VERSION 5.7 ;
  NOWIREEXTENSIONATPIN ON ;
  DIVIDERCHAR "/" ;
  BUSBITCHARS "[]" ;
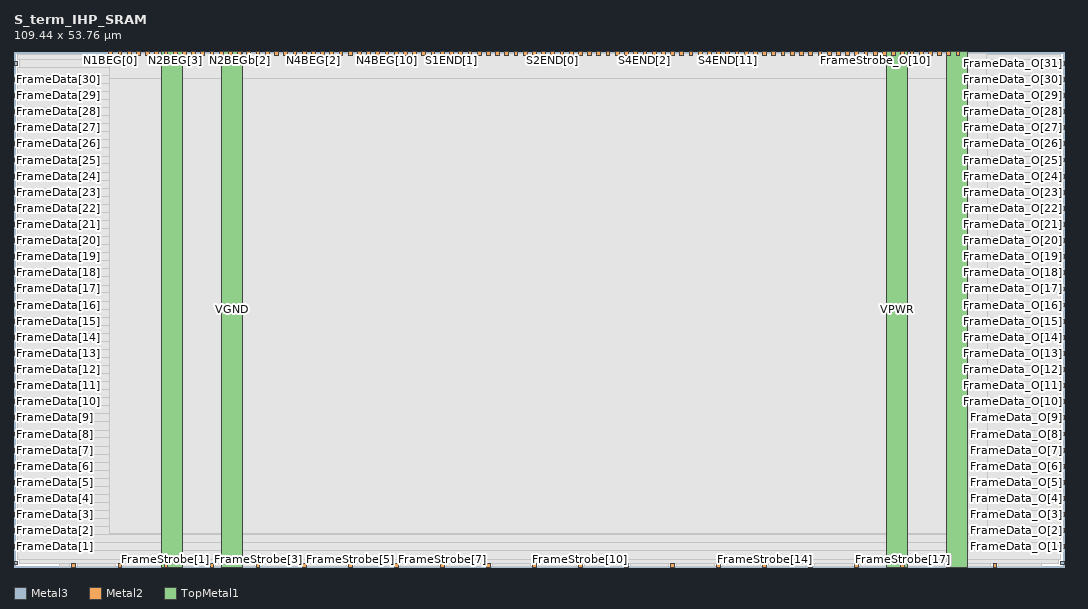
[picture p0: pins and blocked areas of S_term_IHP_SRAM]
MACRO S_term_IHP_SRAM
  CLASS BLOCK ;
  FOREIGN S_term_IHP_SRAM ;
  ORIGIN 0.000 0.000 ;
  SIZE 109.440 BY 53.760 ;
  PIN FrameData[0]
    DIRECTION INPUT ;
    USE SIGNAL ;
    ANTENNAGATEAREA 0.180700 ;
    PORT
      LAYER Metal3 ;
        RECT 0.000 0.220 0.400 0.620 ;
    END
  END FrameData[0]
  PIN FrameData[10]
    DIRECTION INPUT ;
    USE SIGNAL ;
    ANTENNAGATEAREA 0.180700 ;
    PORT
      LAYER Metal3 ;
        RECT 0.000 17.020 0.400 17.420 ;
    END
  END FrameData[10]
  PIN FrameData[11]
    DIRECTION INPUT ;
    USE SIGNAL ;
    ANTENNAGATEAREA 0.180700 ;
    PORT
      LAYER Metal3 ;
        RECT 0.000 18.700 0.400 19.100 ;
    END
  END FrameData[11]
  PIN FrameData[12]
    DIRECTION INPUT ;
    USE SIGNAL ;
    ANTENNAGATEAREA 0.180700 ;
    PORT
      LAYER Metal3 ;
        RECT 0.000 20.380 0.400 20.780 ;
    END
  END FrameData[12]
  PIN FrameData[13]
    DIRECTION INPUT ;
    USE SIGNAL ;
    ANTENNAGATEAREA 0.180700 ;
    PORT
      LAYER Metal3 ;
        RECT 0.000 22.060 0.400 22.460 ;
    END
  END FrameData[13]
  PIN FrameData[14]
    DIRECTION INPUT ;
    USE SIGNAL ;
    ANTENNAGATEAREA 0.180700 ;
    PORT
      LAYER Metal3 ;
        RECT 0.000 23.740 0.400 24.140 ;
    END
  END FrameData[14]
  PIN FrameData[15]
    DIRECTION INPUT ;
    USE SIGNAL ;
    ANTENNAGATEAREA 0.180700 ;
    PORT
      LAYER Metal3 ;
        RECT 0.000 25.420 0.400 25.820 ;
    END
  END FrameData[15]
  PIN FrameData[16]
    DIRECTION INPUT ;
    USE SIGNAL ;
    ANTENNAGATEAREA 0.180700 ;
    PORT
      LAYER Metal3 ;
        RECT 0.000 27.100 0.400 27.500 ;
    END
  END FrameData[16]
  PIN FrameData[17]
    DIRECTION INPUT ;
    USE SIGNAL ;
    ANTENNAGATEAREA 0.180700 ;
    PORT
      LAYER Metal3 ;
        RECT 0.000 28.780 0.400 29.180 ;
    END
  END FrameData[17]
  PIN FrameData[18]
    DIRECTION INPUT ;
    USE SIGNAL ;
    ANTENNAGATEAREA 0.180700 ;
    PORT
      LAYER Metal3 ;
        RECT 0.000 30.460 0.400 30.860 ;
    END
  END FrameData[18]
  PIN FrameData[19]
    DIRECTION INPUT ;
    USE SIGNAL ;
    ANTENNAGATEAREA 0.180700 ;
    PORT
      LAYER Metal3 ;
        RECT 0.000 32.140 0.400 32.540 ;
    END
  END FrameData[19]
  PIN FrameData[1]
    DIRECTION INPUT ;
    USE SIGNAL ;
    ANTENNAGATEAREA 0.180700 ;
    PORT
      LAYER Metal3 ;
        RECT 0.000 1.900 0.400 2.300 ;
    END
  END FrameData[1]
  PIN FrameData[20]
    DIRECTION INPUT ;
    USE SIGNAL ;
    ANTENNAGATEAREA 0.180700 ;
    PORT
      LAYER Metal3 ;
        RECT 0.000 33.820 0.400 34.220 ;
    END
  END FrameData[20]
  PIN FrameData[21]
    DIRECTION INPUT ;
    USE SIGNAL ;
    ANTENNAGATEAREA 0.180700 ;
    PORT
      LAYER Metal3 ;
        RECT 0.000 35.500 0.400 35.900 ;
    END
  END FrameData[21]
  PIN FrameData[22]
    DIRECTION INPUT ;
    USE SIGNAL ;
    ANTENNAGATEAREA 0.180700 ;
    PORT
      LAYER Metal3 ;
        RECT 0.000 37.180 0.400 37.580 ;
    END
  END FrameData[22]
  PIN FrameData[23]
    DIRECTION INPUT ;
    USE SIGNAL ;
    ANTENNAGATEAREA 0.180700 ;
    PORT
      LAYER Metal3 ;
        RECT 0.000 38.860 0.400 39.260 ;
    END
  END FrameData[23]
  PIN FrameData[24]
    DIRECTION INPUT ;
    USE SIGNAL ;
    ANTENNAGATEAREA 0.180700 ;
    PORT
      LAYER Metal3 ;
        RECT 0.000 40.540 0.400 40.940 ;
    END
  END FrameData[24]
  PIN FrameData[25]
    DIRECTION INPUT ;
    USE SIGNAL ;
    ANTENNAGATEAREA 0.180700 ;
    PORT
      LAYER Metal3 ;
        RECT 0.000 42.220 0.400 42.620 ;
    END
  END FrameData[25]
  PIN FrameData[26]
    DIRECTION INPUT ;
    USE SIGNAL ;
    ANTENNAGATEAREA 0.180700 ;
    PORT
      LAYER Metal3 ;
        RECT 0.000 43.900 0.400 44.300 ;
    END
  END FrameData[26]
  PIN FrameData[27]
    DIRECTION INPUT ;
    USE SIGNAL ;
    ANTENNAGATEAREA 0.180700 ;
    PORT
      LAYER Metal3 ;
        RECT 0.000 45.580 0.400 45.980 ;
    END
  END FrameData[27]
  PIN FrameData[28]
    DIRECTION INPUT ;
    USE SIGNAL ;
    ANTENNAGATEAREA 0.180700 ;
    PORT
      LAYER Metal3 ;
        RECT 0.000 47.260 0.400 47.660 ;
    END
  END FrameData[28]
  PIN FrameData[29]
    DIRECTION INPUT ;
    USE SIGNAL ;
    ANTENNAGATEAREA 0.180700 ;
    PORT
      LAYER Metal3 ;
        RECT 0.000 48.940 0.400 49.340 ;
    END
  END FrameData[29]
  PIN FrameData[2]
    DIRECTION INPUT ;
    USE SIGNAL ;
    ANTENNAGATEAREA 0.180700 ;
    PORT
      LAYER Metal3 ;
        RECT 0.000 3.580 0.400 3.980 ;
    END
  END FrameData[2]
  PIN FrameData[30]
    DIRECTION INPUT ;
    USE SIGNAL ;
    ANTENNAGATEAREA 0.180700 ;
    PORT
      LAYER Metal3 ;
        RECT 0.000 50.620 0.400 51.020 ;
    END
  END FrameData[30]
  PIN FrameData[31]
    DIRECTION INPUT ;
    USE SIGNAL ;
    ANTENNAGATEAREA 0.180700 ;
    PORT
      LAYER Metal3 ;
        RECT 0.000 52.300 0.400 52.700 ;
    END
  END FrameData[31]
  PIN FrameData[3]
    DIRECTION INPUT ;
    USE SIGNAL ;
    ANTENNAGATEAREA 0.180700 ;
    PORT
      LAYER Metal3 ;
        RECT 0.000 5.260 0.400 5.660 ;
    END
  END FrameData[3]
  PIN FrameData[4]
    DIRECTION INPUT ;
    USE SIGNAL ;
    ANTENNAGATEAREA 0.180700 ;
    PORT
      LAYER Metal3 ;
        RECT 0.000 6.940 0.400 7.340 ;
    END
  END FrameData[4]
  PIN FrameData[5]
    DIRECTION INPUT ;
    USE SIGNAL ;
    ANTENNAGATEAREA 0.180700 ;
    PORT
      LAYER Metal3 ;
        RECT 0.000 8.620 0.400 9.020 ;
    END
  END FrameData[5]
  PIN FrameData[6]
    DIRECTION INPUT ;
    USE SIGNAL ;
    ANTENNAGATEAREA 0.180700 ;
    PORT
      LAYER Metal3 ;
        RECT 0.000 10.300 0.400 10.700 ;
    END
  END FrameData[6]
  PIN FrameData[7]
    DIRECTION INPUT ;
    USE SIGNAL ;
    ANTENNAGATEAREA 0.180700 ;
    PORT
      LAYER Metal3 ;
        RECT 0.000 11.980 0.400 12.380 ;
    END
  END FrameData[7]
  PIN FrameData[8]
    DIRECTION INPUT ;
    USE SIGNAL ;
    ANTENNAGATEAREA 0.180700 ;
    PORT
      LAYER Metal3 ;
        RECT 0.000 13.660 0.400 14.060 ;
    END
  END FrameData[8]
  PIN FrameData[9]
    DIRECTION INPUT ;
    USE SIGNAL ;
    ANTENNAGATEAREA 0.180700 ;
    PORT
      LAYER Metal3 ;
        RECT 0.000 15.340 0.400 15.740 ;
    END
  END FrameData[9]
  PIN FrameData_O[0]
    DIRECTION OUTPUT ;
    USE SIGNAL ;
    ANTENNADIFFAREA 0.708600 ;
    PORT
      LAYER Metal3 ;
        RECT 109.040 0.220 109.440 0.620 ;
    END
  END FrameData_O[0]
  PIN FrameData_O[10]
    DIRECTION OUTPUT ;
    USE SIGNAL ;
    ANTENNADIFFAREA 0.708600 ;
    PORT
      LAYER Metal3 ;
        RECT 109.040 17.020 109.440 17.420 ;
    END
  END FrameData_O[10]
  PIN FrameData_O[11]
    DIRECTION OUTPUT ;
    USE SIGNAL ;
    ANTENNADIFFAREA 0.708600 ;
    PORT
      LAYER Metal3 ;
        RECT 109.040 18.700 109.440 19.100 ;
    END
  END FrameData_O[11]
  PIN FrameData_O[12]
    DIRECTION OUTPUT ;
    USE SIGNAL ;
    ANTENNADIFFAREA 0.708600 ;
    PORT
      LAYER Metal3 ;
        RECT 109.040 20.380 109.440 20.780 ;
    END
  END FrameData_O[12]
  PIN FrameData_O[13]
    DIRECTION OUTPUT ;
    USE SIGNAL ;
    ANTENNADIFFAREA 0.708600 ;
    PORT
      LAYER Metal3 ;
        RECT 109.040 22.060 109.440 22.460 ;
    END
  END FrameData_O[13]
  PIN FrameData_O[14]
    DIRECTION OUTPUT ;
    USE SIGNAL ;
    ANTENNADIFFAREA 0.708600 ;
    PORT
      LAYER Metal3 ;
        RECT 109.040 23.740 109.440 24.140 ;
    END
  END FrameData_O[14]
  PIN FrameData_O[15]
    DIRECTION OUTPUT ;
    USE SIGNAL ;
    ANTENNADIFFAREA 0.708600 ;
    PORT
      LAYER Metal3 ;
        RECT 109.040 25.420 109.440 25.820 ;
    END
  END FrameData_O[15]
  PIN FrameData_O[16]
    DIRECTION OUTPUT ;
    USE SIGNAL ;
    ANTENNADIFFAREA 0.708600 ;
    PORT
      LAYER Metal3 ;
        RECT 109.040 27.100 109.440 27.500 ;
    END
  END FrameData_O[16]
  PIN FrameData_O[17]
    DIRECTION OUTPUT ;
    USE SIGNAL ;
    ANTENNADIFFAREA 0.708600 ;
    PORT
      LAYER Metal3 ;
        RECT 109.040 28.780 109.440 29.180 ;
    END
  END FrameData_O[17]
  PIN FrameData_O[18]
    DIRECTION OUTPUT ;
    USE SIGNAL ;
    ANTENNADIFFAREA 0.708600 ;
    PORT
      LAYER Metal3 ;
        RECT 109.040 30.460 109.440 30.860 ;
    END
  END FrameData_O[18]
  PIN FrameData_O[19]
    DIRECTION OUTPUT ;
    USE SIGNAL ;
    ANTENNADIFFAREA 0.708600 ;
    PORT
      LAYER Metal3 ;
        RECT 109.040 32.140 109.440 32.540 ;
    END
  END FrameData_O[19]
  PIN FrameData_O[1]
    DIRECTION OUTPUT ;
    USE SIGNAL ;
    ANTENNADIFFAREA 0.708600 ;
    PORT
      LAYER Metal3 ;
        RECT 109.040 1.900 109.440 2.300 ;
    END
  END FrameData_O[1]
  PIN FrameData_O[20]
    DIRECTION OUTPUT ;
    USE SIGNAL ;
    ANTENNADIFFAREA 0.708600 ;
    PORT
      LAYER Metal3 ;
        RECT 109.040 33.820 109.440 34.220 ;
    END
  END FrameData_O[20]
  PIN FrameData_O[21]
    DIRECTION OUTPUT ;
    USE SIGNAL ;
    ANTENNADIFFAREA 0.708600 ;
    PORT
      LAYER Metal3 ;
        RECT 109.040 35.500 109.440 35.900 ;
    END
  END FrameData_O[21]
  PIN FrameData_O[22]
    DIRECTION OUTPUT ;
    USE SIGNAL ;
    ANTENNADIFFAREA 0.708600 ;
    PORT
      LAYER Metal3 ;
        RECT 109.040 37.180 109.440 37.580 ;
    END
  END FrameData_O[22]
  PIN FrameData_O[23]
    DIRECTION OUTPUT ;
    USE SIGNAL ;
    ANTENNADIFFAREA 0.708600 ;
    PORT
      LAYER Metal3 ;
        RECT 109.040 38.860 109.440 39.260 ;
    END
  END FrameData_O[23]
  PIN FrameData_O[24]
    DIRECTION OUTPUT ;
    USE SIGNAL ;
    ANTENNADIFFAREA 0.708600 ;
    PORT
      LAYER Metal3 ;
        RECT 109.040 40.540 109.440 40.940 ;
    END
  END FrameData_O[24]
  PIN FrameData_O[25]
    DIRECTION OUTPUT ;
    USE SIGNAL ;
    ANTENNADIFFAREA 0.708600 ;
    PORT
      LAYER Metal3 ;
        RECT 109.040 42.220 109.440 42.620 ;
    END
  END FrameData_O[25]
  PIN FrameData_O[26]
    DIRECTION OUTPUT ;
    USE SIGNAL ;
    ANTENNADIFFAREA 0.708600 ;
    PORT
      LAYER Metal3 ;
        RECT 109.040 43.900 109.440 44.300 ;
    END
  END FrameData_O[26]
  PIN FrameData_O[27]
    DIRECTION OUTPUT ;
    USE SIGNAL ;
    ANTENNADIFFAREA 0.708600 ;
    PORT
      LAYER Metal3 ;
        RECT 109.040 45.580 109.440 45.980 ;
    END
  END FrameData_O[27]
  PIN FrameData_O[28]
    DIRECTION OUTPUT ;
    USE SIGNAL ;
    ANTENNADIFFAREA 0.708600 ;
    PORT
      LAYER Metal3 ;
        RECT 109.040 47.260 109.440 47.660 ;
    END
  END FrameData_O[28]
  PIN FrameData_O[29]
    DIRECTION OUTPUT ;
    USE SIGNAL ;
    ANTENNADIFFAREA 0.708600 ;
    PORT
      LAYER Metal3 ;
        RECT 109.040 48.940 109.440 49.340 ;
    END
  END FrameData_O[29]
  PIN FrameData_O[2]
    DIRECTION OUTPUT ;
    USE SIGNAL ;
    ANTENNADIFFAREA 0.708600 ;
    PORT
      LAYER Metal3 ;
        RECT 109.040 3.580 109.440 3.980 ;
    END
  END FrameData_O[2]
  PIN FrameData_O[30]
    DIRECTION OUTPUT ;
    USE SIGNAL ;
    ANTENNADIFFAREA 0.708600 ;
    PORT
      LAYER Metal3 ;
        RECT 109.040 50.620 109.440 51.020 ;
    END
  END FrameData_O[30]
  PIN FrameData_O[31]
    DIRECTION OUTPUT ;
    USE SIGNAL ;
    ANTENNADIFFAREA 0.708600 ;
    PORT
      LAYER Metal3 ;
        RECT 109.040 52.300 109.440 52.700 ;
    END
  END FrameData_O[31]
  PIN FrameData_O[3]
    DIRECTION OUTPUT ;
    USE SIGNAL ;
    ANTENNADIFFAREA 0.708600 ;
    PORT
      LAYER Metal3 ;
        RECT 109.040 5.260 109.440 5.660 ;
    END
  END FrameData_O[3]
  PIN FrameData_O[4]
    DIRECTION OUTPUT ;
    USE SIGNAL ;
    ANTENNADIFFAREA 0.708600 ;
    PORT
      LAYER Metal3 ;
        RECT 109.040 6.940 109.440 7.340 ;
    END
  END FrameData_O[4]
  PIN FrameData_O[5]
    DIRECTION OUTPUT ;
    USE SIGNAL ;
    ANTENNADIFFAREA 0.708600 ;
    PORT
      LAYER Metal3 ;
        RECT 109.040 8.620 109.440 9.020 ;
    END
  END FrameData_O[5]
  PIN FrameData_O[6]
    DIRECTION OUTPUT ;
    USE SIGNAL ;
    ANTENNADIFFAREA 0.708600 ;
    PORT
      LAYER Metal3 ;
        RECT 109.040 10.300 109.440 10.700 ;
    END
  END FrameData_O[6]
  PIN FrameData_O[7]
    DIRECTION OUTPUT ;
    USE SIGNAL ;
    ANTENNADIFFAREA 0.708600 ;
    PORT
      LAYER Metal3 ;
        RECT 109.040 11.980 109.440 12.380 ;
    END
  END FrameData_O[7]
  PIN FrameData_O[8]
    DIRECTION OUTPUT ;
    USE SIGNAL ;
    ANTENNADIFFAREA 0.708600 ;
    PORT
      LAYER Metal3 ;
        RECT 109.040 13.660 109.440 14.060 ;
    END
  END FrameData_O[8]
  PIN FrameData_O[9]
    DIRECTION OUTPUT ;
    USE SIGNAL ;
    ANTENNADIFFAREA 0.708600 ;
    PORT
      LAYER Metal3 ;
        RECT 109.040 15.340 109.440 15.740 ;
    END
  END FrameData_O[9]
  PIN FrameStrobe[0]
    DIRECTION INPUT ;
    USE SIGNAL ;
    ANTENNAGATEAREA 0.180700 ;
    PORT
      LAYER Metal2 ;
        RECT 10.840 0.000 11.240 0.400 ;
    END
  END FrameStrobe[0]
  PIN FrameStrobe[10]
    DIRECTION INPUT ;
    USE SIGNAL ;
    ANTENNAGATEAREA 0.180700 ;
    PORT
      LAYER Metal2 ;
        RECT 58.840 0.000 59.240 0.400 ;
    END
  END FrameStrobe[10]
  PIN FrameStrobe[11]
    DIRECTION INPUT ;
    USE SIGNAL ;
    ANTENNAGATEAREA 0.180700 ;
    PORT
      LAYER Metal2 ;
        RECT 63.640 0.000 64.040 0.400 ;
    END
  END FrameStrobe[11]
  PIN FrameStrobe[12]
    DIRECTION INPUT ;
    USE SIGNAL ;
    ANTENNAGATEAREA 0.180700 ;
    PORT
      LAYER Metal2 ;
        RECT 68.440 0.000 68.840 0.400 ;
    END
  END FrameStrobe[12]
  PIN FrameStrobe[13]
    DIRECTION INPUT ;
    USE SIGNAL ;
    ANTENNAGATEAREA 0.180700 ;
    PORT
      LAYER Metal2 ;
        RECT 73.240 0.000 73.640 0.400 ;
    END
  END FrameStrobe[13]
  PIN FrameStrobe[14]
    DIRECTION INPUT ;
    USE SIGNAL ;
    ANTENNAGATEAREA 0.180700 ;
    PORT
      LAYER Metal2 ;
        RECT 78.040 0.000 78.440 0.400 ;
    END
  END FrameStrobe[14]
  PIN FrameStrobe[15]
    DIRECTION INPUT ;
    USE SIGNAL ;
    ANTENNAGATEAREA 0.180700 ;
    PORT
      LAYER Metal2 ;
        RECT 82.840 0.000 83.240 0.400 ;
    END
  END FrameStrobe[15]
  PIN FrameStrobe[16]
    DIRECTION INPUT ;
    USE SIGNAL ;
    ANTENNAGATEAREA 0.180700 ;
    PORT
      LAYER Metal2 ;
        RECT 87.640 0.000 88.040 0.400 ;
    END
  END FrameStrobe[16]
  PIN FrameStrobe[17]
    DIRECTION INPUT ;
    USE SIGNAL ;
    ANTENNAGATEAREA 0.180700 ;
    PORT
      LAYER Metal2 ;
        RECT 92.440 0.000 92.840 0.400 ;
    END
  END FrameStrobe[17]
  PIN FrameStrobe[18]
    DIRECTION INPUT ;
    USE SIGNAL ;
    ANTENNAGATEAREA 0.180700 ;
    PORT
      LAYER Metal2 ;
        RECT 97.240 0.000 97.640 0.400 ;
    END
  END FrameStrobe[18]
  PIN FrameStrobe[19]
    DIRECTION INPUT ;
    USE SIGNAL ;
    ANTENNAGATEAREA 0.180700 ;
    PORT
      LAYER Metal2 ;
        RECT 102.040 0.000 102.440 0.400 ;
    END
  END FrameStrobe[19]
  PIN FrameStrobe[1]
    DIRECTION INPUT ;
    USE SIGNAL ;
    ANTENNAGATEAREA 0.180700 ;
    PORT
      LAYER Metal2 ;
        RECT 15.640 0.000 16.040 0.400 ;
    END
  END FrameStrobe[1]
  PIN FrameStrobe[2]
    DIRECTION INPUT ;
    USE SIGNAL ;
    ANTENNAGATEAREA 0.180700 ;
    PORT
      LAYER Metal2 ;
        RECT 20.440 0.000 20.840 0.400 ;
    END
  END FrameStrobe[2]
  PIN FrameStrobe[3]
    DIRECTION INPUT ;
    USE SIGNAL ;
    ANTENNAGATEAREA 0.180700 ;
    PORT
      LAYER Metal2 ;
        RECT 25.240 0.000 25.640 0.400 ;
    END
  END FrameStrobe[3]
  PIN FrameStrobe[4]
    DIRECTION INPUT ;
    USE SIGNAL ;
    ANTENNAGATEAREA 0.180700 ;
    PORT
      LAYER Metal2 ;
        RECT 30.040 0.000 30.440 0.400 ;
    END
  END FrameStrobe[4]
  PIN FrameStrobe[5]
    DIRECTION INPUT ;
    USE SIGNAL ;
    ANTENNAGATEAREA 0.180700 ;
    PORT
      LAYER Metal2 ;
        RECT 34.840 0.000 35.240 0.400 ;
    END
  END FrameStrobe[5]
  PIN FrameStrobe[6]
    DIRECTION INPUT ;
    USE SIGNAL ;
    ANTENNAGATEAREA 0.180700 ;
    PORT
      LAYER Metal2 ;
        RECT 39.640 0.000 40.040 0.400 ;
    END
  END FrameStrobe[6]
  PIN FrameStrobe[7]
    DIRECTION INPUT ;
    USE SIGNAL ;
    ANTENNAGATEAREA 0.180700 ;
    PORT
      LAYER Metal2 ;
        RECT 44.440 0.000 44.840 0.400 ;
    END
  END FrameStrobe[7]
  PIN FrameStrobe[8]
    DIRECTION INPUT ;
    USE SIGNAL ;
    ANTENNAGATEAREA 0.180700 ;
    PORT
      LAYER Metal2 ;
        RECT 49.240 0.000 49.640 0.400 ;
    END
  END FrameStrobe[8]
  PIN FrameStrobe[9]
    DIRECTION INPUT ;
    USE SIGNAL ;
    ANTENNAGATEAREA 0.180700 ;
    PORT
      LAYER Metal2 ;
        RECT 54.040 0.000 54.440 0.400 ;
    END
  END FrameStrobe[9]
  PIN FrameStrobe_O[0]
    DIRECTION OUTPUT ;
    USE SIGNAL ;
    ANTENNADIFFAREA 0.708600 ;
    PORT
      LAYER Metal2 ;
        RECT 79.960 53.360 80.360 53.760 ;
    END
  END FrameStrobe_O[0]
  PIN FrameStrobe_O[10]
    DIRECTION OUTPUT ;
    USE SIGNAL ;
    ANTENNADIFFAREA 0.708600 ;
    PORT
      LAYER Metal2 ;
        RECT 89.560 53.360 89.960 53.760 ;
    END
  END FrameStrobe_O[10]
  PIN FrameStrobe_O[11]
    DIRECTION OUTPUT ;
    USE SIGNAL ;
    ANTENNADIFFAREA 0.708600 ;
    PORT
      LAYER Metal2 ;
        RECT 90.520 53.360 90.920 53.760 ;
    END
  END FrameStrobe_O[11]
  PIN FrameStrobe_O[12]
    DIRECTION OUTPUT ;
    USE SIGNAL ;
    ANTENNADIFFAREA 0.708600 ;
    PORT
      LAYER Metal2 ;
        RECT 91.480 53.360 91.880 53.760 ;
    END
  END FrameStrobe_O[12]
  PIN FrameStrobe_O[13]
    DIRECTION OUTPUT ;
    USE SIGNAL ;
    ANTENNADIFFAREA 0.708600 ;
    PORT
      LAYER Metal2 ;
        RECT 92.440 53.360 92.840 53.760 ;
    END
  END FrameStrobe_O[13]
  PIN FrameStrobe_O[14]
    DIRECTION OUTPUT ;
    USE SIGNAL ;
    ANTENNADIFFAREA 0.708600 ;
    PORT
      LAYER Metal2 ;
        RECT 93.400 53.360 93.800 53.760 ;
    END
  END FrameStrobe_O[14]
  PIN FrameStrobe_O[15]
    DIRECTION OUTPUT ;
    USE SIGNAL ;
    ANTENNADIFFAREA 0.708600 ;
    PORT
      LAYER Metal2 ;
        RECT 94.360 53.360 94.760 53.760 ;
    END
  END FrameStrobe_O[15]
  PIN FrameStrobe_O[16]
    DIRECTION OUTPUT ;
    USE SIGNAL ;
    ANTENNADIFFAREA 0.708600 ;
    PORT
      LAYER Metal2 ;
        RECT 95.320 53.360 95.720 53.760 ;
    END
  END FrameStrobe_O[16]
  PIN FrameStrobe_O[17]
    DIRECTION OUTPUT ;
    USE SIGNAL ;
    ANTENNADIFFAREA 0.708600 ;
    PORT
      LAYER Metal2 ;
        RECT 96.280 53.360 96.680 53.760 ;
    END
  END FrameStrobe_O[17]
  PIN FrameStrobe_O[18]
    DIRECTION OUTPUT ;
    USE SIGNAL ;
    ANTENNADIFFAREA 0.708600 ;
    PORT
      LAYER Metal2 ;
        RECT 97.240 53.360 97.640 53.760 ;
    END
  END FrameStrobe_O[18]
  PIN FrameStrobe_O[19]
    DIRECTION OUTPUT ;
    USE SIGNAL ;
    ANTENNADIFFAREA 0.708600 ;
    PORT
      LAYER Metal2 ;
        RECT 98.200 53.360 98.600 53.760 ;
    END
  END FrameStrobe_O[19]
  PIN FrameStrobe_O[1]
    DIRECTION OUTPUT ;
    USE SIGNAL ;
    ANTENNADIFFAREA 0.708600 ;
    PORT
      LAYER Metal2 ;
        RECT 80.920 53.360 81.320 53.760 ;
    END
  END FrameStrobe_O[1]
  PIN FrameStrobe_O[2]
    DIRECTION OUTPUT ;
    USE SIGNAL ;
    ANTENNADIFFAREA 0.708600 ;
    PORT
      LAYER Metal2 ;
        RECT 81.880 53.360 82.280 53.760 ;
    END
  END FrameStrobe_O[2]
  PIN FrameStrobe_O[3]
    DIRECTION OUTPUT ;
    USE SIGNAL ;
    ANTENNADIFFAREA 0.708600 ;
    PORT
      LAYER Metal2 ;
        RECT 82.840 53.360 83.240 53.760 ;
    END
  END FrameStrobe_O[3]
  PIN FrameStrobe_O[4]
    DIRECTION OUTPUT ;
    USE SIGNAL ;
    ANTENNADIFFAREA 0.708600 ;
    PORT
      LAYER Metal2 ;
        RECT 83.800 53.360 84.200 53.760 ;
    END
  END FrameStrobe_O[4]
  PIN FrameStrobe_O[5]
    DIRECTION OUTPUT ;
    USE SIGNAL ;
    ANTENNADIFFAREA 0.708600 ;
    PORT
      LAYER Metal2 ;
        RECT 84.760 53.360 85.160 53.760 ;
    END
  END FrameStrobe_O[5]
  PIN FrameStrobe_O[6]
    DIRECTION OUTPUT ;
    USE SIGNAL ;
    ANTENNADIFFAREA 0.708600 ;
    PORT
      LAYER Metal2 ;
        RECT 85.720 53.360 86.120 53.760 ;
    END
  END FrameStrobe_O[6]
  PIN FrameStrobe_O[7]
    DIRECTION OUTPUT ;
    USE SIGNAL ;
    ANTENNADIFFAREA 0.708600 ;
    PORT
      LAYER Metal2 ;
        RECT 86.680 53.360 87.080 53.760 ;
    END
  END FrameStrobe_O[7]
  PIN FrameStrobe_O[8]
    DIRECTION OUTPUT ;
    USE SIGNAL ;
    ANTENNADIFFAREA 0.708600 ;
    PORT
      LAYER Metal2 ;
        RECT 87.640 53.360 88.040 53.760 ;
    END
  END FrameStrobe_O[8]
  PIN FrameStrobe_O[9]
    DIRECTION OUTPUT ;
    USE SIGNAL ;
    ANTENNADIFFAREA 0.708600 ;
    PORT
      LAYER Metal2 ;
        RECT 88.600 53.360 89.000 53.760 ;
    END
  END FrameStrobe_O[9]
  PIN N1BEG[0]
    DIRECTION OUTPUT ;
    USE SIGNAL ;
    ANTENNADIFFAREA 0.708600 ;
    PORT
      LAYER Metal2 ;
        RECT 9.880 53.360 10.280 53.760 ;
    END
  END N1BEG[0]
  PIN N1BEG[1]
    DIRECTION OUTPUT ;
    USE SIGNAL ;
    ANTENNADIFFAREA 0.708600 ;
    PORT
      LAYER Metal2 ;
        RECT 10.840 53.360 11.240 53.760 ;
    END
  END N1BEG[1]
  PIN N1BEG[2]
    DIRECTION OUTPUT ;
    USE SIGNAL ;
    ANTENNADIFFAREA 0.708600 ;
    PORT
      LAYER Metal2 ;
        RECT 11.800 53.360 12.200 53.760 ;
    END
  END N1BEG[2]
  PIN N1BEG[3]
    DIRECTION OUTPUT ;
    USE SIGNAL ;
    ANTENNADIFFAREA 0.708600 ;
    PORT
      LAYER Metal2 ;
        RECT 12.760 53.360 13.160 53.760 ;
    END
  END N1BEG[3]
  PIN N2BEG[0]
    DIRECTION OUTPUT ;
    USE SIGNAL ;
    ANTENNADIFFAREA 0.708600 ;
    PORT
      LAYER Metal2 ;
        RECT 13.720 53.360 14.120 53.760 ;
    END
  END N2BEG[0]
  PIN N2BEG[1]
    DIRECTION OUTPUT ;
    USE SIGNAL ;
    ANTENNADIFFAREA 0.708600 ;
    PORT
      LAYER Metal2 ;
        RECT 14.680 53.360 15.080 53.760 ;
    END
  END N2BEG[1]
  PIN N2BEG[2]
    DIRECTION OUTPUT ;
    USE SIGNAL ;
    ANTENNADIFFAREA 0.708600 ;
    PORT
      LAYER Metal2 ;
        RECT 15.640 53.360 16.040 53.760 ;
    END
  END N2BEG[2]
  PIN N2BEG[3]
    DIRECTION OUTPUT ;
    USE SIGNAL ;
    ANTENNADIFFAREA 0.708600 ;
    PORT
      LAYER Metal2 ;
        RECT 16.600 53.360 17.000 53.760 ;
    END
  END N2BEG[3]
  PIN N2BEG[4]
    DIRECTION OUTPUT ;
    USE SIGNAL ;
    ANTENNADIFFAREA 0.708600 ;
    PORT
      LAYER Metal2 ;
        RECT 17.560 53.360 17.960 53.760 ;
    END
  END N2BEG[4]
  PIN N2BEG[5]
    DIRECTION OUTPUT ;
    USE SIGNAL ;
    ANTENNADIFFAREA 0.708600 ;
    PORT
      LAYER Metal2 ;
        RECT 18.520 53.360 18.920 53.760 ;
    END
  END N2BEG[5]
  PIN N2BEG[6]
    DIRECTION OUTPUT ;
    USE SIGNAL ;
    ANTENNADIFFAREA 0.708600 ;
    PORT
      LAYER Metal2 ;
        RECT 19.480 53.360 19.880 53.760 ;
    END
  END N2BEG[6]
  PIN N2BEG[7]
    DIRECTION OUTPUT ;
    USE SIGNAL ;
    ANTENNADIFFAREA 0.708600 ;
    PORT
      LAYER Metal2 ;
        RECT 20.440 53.360 20.840 53.760 ;
    END
  END N2BEG[7]
  PIN N2BEGb[0]
    DIRECTION OUTPUT ;
    USE SIGNAL ;
    ANTENNADIFFAREA 0.708600 ;
    PORT
      LAYER Metal2 ;
        RECT 21.400 53.360 21.800 53.760 ;
    END
  END N2BEGb[0]
  PIN N2BEGb[1]
    DIRECTION OUTPUT ;
    USE SIGNAL ;
    ANTENNADIFFAREA 0.708600 ;
    PORT
      LAYER Metal2 ;
        RECT 22.360 53.360 22.760 53.760 ;
    END
  END N2BEGb[1]
  PIN N2BEGb[2]
    DIRECTION OUTPUT ;
    USE SIGNAL ;
    ANTENNADIFFAREA 0.708600 ;
    PORT
      LAYER Metal2 ;
        RECT 23.320 53.360 23.720 53.760 ;
    END
  END N2BEGb[2]
  PIN N2BEGb[3]
    DIRECTION OUTPUT ;
    USE SIGNAL ;
    ANTENNADIFFAREA 0.708600 ;
    PORT
      LAYER Metal2 ;
        RECT 24.280 53.360 24.680 53.760 ;
    END
  END N2BEGb[3]
  PIN N2BEGb[4]
    DIRECTION OUTPUT ;
    USE SIGNAL ;
    ANTENNADIFFAREA 0.708600 ;
    PORT
      LAYER Metal2 ;
        RECT 25.240 53.360 25.640 53.760 ;
    END
  END N2BEGb[4]
  PIN N2BEGb[5]
    DIRECTION OUTPUT ;
    USE SIGNAL ;
    ANTENNADIFFAREA 0.708600 ;
    PORT
      LAYER Metal2 ;
        RECT 26.200 53.360 26.600 53.760 ;
    END
  END N2BEGb[5]
  PIN N2BEGb[6]
    DIRECTION OUTPUT ;
    USE SIGNAL ;
    ANTENNADIFFAREA 0.708600 ;
    PORT
      LAYER Metal2 ;
        RECT 27.160 53.360 27.560 53.760 ;
    END
  END N2BEGb[6]
  PIN N2BEGb[7]
    DIRECTION OUTPUT ;
    USE SIGNAL ;
    ANTENNADIFFAREA 0.708600 ;
    PORT
      LAYER Metal2 ;
        RECT 28.120 53.360 28.520 53.760 ;
    END
  END N2BEGb[7]
  PIN N4BEG[0]
    DIRECTION OUTPUT ;
    USE SIGNAL ;
    ANTENNADIFFAREA 0.708600 ;
    PORT
      LAYER Metal2 ;
        RECT 29.080 53.360 29.480 53.760 ;
    END
  END N4BEG[0]
  PIN N4BEG[10]
    DIRECTION OUTPUT ;
    USE SIGNAL ;
    ANTENNADIFFAREA 0.708600 ;
    PORT
      LAYER Metal2 ;
        RECT 38.680 53.360 39.080 53.760 ;
    END
  END N4BEG[10]
  PIN N4BEG[11]
    DIRECTION OUTPUT ;
    USE SIGNAL ;
    ANTENNADIFFAREA 0.708600 ;
    PORT
      LAYER Metal2 ;
        RECT 39.640 53.360 40.040 53.760 ;
    END
  END N4BEG[11]
  PIN N4BEG[12]
    DIRECTION OUTPUT ;
    USE SIGNAL ;
    ANTENNADIFFAREA 0.708600 ;
    PORT
      LAYER Metal2 ;
        RECT 40.600 53.360 41.000 53.760 ;
    END
  END N4BEG[12]
  PIN N4BEG[13]
    DIRECTION OUTPUT ;
    USE SIGNAL ;
    ANTENNADIFFAREA 0.708600 ;
    PORT
      LAYER Metal2 ;
        RECT 41.560 53.360 41.960 53.760 ;
    END
  END N4BEG[13]
  PIN N4BEG[14]
    DIRECTION OUTPUT ;
    USE SIGNAL ;
    ANTENNADIFFAREA 0.708600 ;
    PORT
      LAYER Metal2 ;
        RECT 42.520 53.360 42.920 53.760 ;
    END
  END N4BEG[14]
  PIN N4BEG[15]
    DIRECTION OUTPUT ;
    USE SIGNAL ;
    ANTENNADIFFAREA 0.708600 ;
    PORT
      LAYER Metal2 ;
        RECT 43.480 53.360 43.880 53.760 ;
    END
  END N4BEG[15]
  PIN N4BEG[1]
    DIRECTION OUTPUT ;
    USE SIGNAL ;
    ANTENNADIFFAREA 0.708600 ;
    PORT
      LAYER Metal2 ;
        RECT 30.040 53.360 30.440 53.760 ;
    END
  END N4BEG[1]
  PIN N4BEG[2]
    DIRECTION OUTPUT ;
    USE SIGNAL ;
    ANTENNADIFFAREA 0.708600 ;
    PORT
      LAYER Metal2 ;
        RECT 31.000 53.360 31.400 53.760 ;
    END
  END N4BEG[2]
  PIN N4BEG[3]
    DIRECTION OUTPUT ;
    USE SIGNAL ;
    ANTENNADIFFAREA 0.708600 ;
    PORT
      LAYER Metal2 ;
        RECT 31.960 53.360 32.360 53.760 ;
    END
  END N4BEG[3]
  PIN N4BEG[4]
    DIRECTION OUTPUT ;
    USE SIGNAL ;
    ANTENNADIFFAREA 0.708600 ;
    PORT
      LAYER Metal2 ;
        RECT 32.920 53.360 33.320 53.760 ;
    END
  END N4BEG[4]
  PIN N4BEG[5]
    DIRECTION OUTPUT ;
    USE SIGNAL ;
    ANTENNADIFFAREA 0.708600 ;
    PORT
      LAYER Metal2 ;
        RECT 33.880 53.360 34.280 53.760 ;
    END
  END N4BEG[5]
  PIN N4BEG[6]
    DIRECTION OUTPUT ;
    USE SIGNAL ;
    ANTENNADIFFAREA 0.708600 ;
    PORT
      LAYER Metal2 ;
        RECT 34.840 53.360 35.240 53.760 ;
    END
  END N4BEG[6]
  PIN N4BEG[7]
    DIRECTION OUTPUT ;
    USE SIGNAL ;
    ANTENNADIFFAREA 0.708600 ;
    PORT
      LAYER Metal2 ;
        RECT 35.800 53.360 36.200 53.760 ;
    END
  END N4BEG[7]
  PIN N4BEG[8]
    DIRECTION OUTPUT ;
    USE SIGNAL ;
    ANTENNADIFFAREA 0.708600 ;
    PORT
      LAYER Metal2 ;
        RECT 36.760 53.360 37.160 53.760 ;
    END
  END N4BEG[8]
  PIN N4BEG[9]
    DIRECTION OUTPUT ;
    USE SIGNAL ;
    ANTENNADIFFAREA 0.708600 ;
    PORT
      LAYER Metal2 ;
        RECT 37.720 53.360 38.120 53.760 ;
    END
  END N4BEG[9]
  PIN S1END[0]
    DIRECTION INPUT ;
    USE SIGNAL ;
    ANTENNAGATEAREA 0.180700 ;
    PORT
      LAYER Metal2 ;
        RECT 44.440 53.360 44.840 53.760 ;
    END
  END S1END[0]
  PIN S1END[1]
    DIRECTION INPUT ;
    USE SIGNAL ;
    ANTENNAGATEAREA 0.180700 ;
    PORT
      LAYER Metal2 ;
        RECT 45.400 53.360 45.800 53.760 ;
    END
  END S1END[1]
  PIN S1END[2]
    DIRECTION INPUT ;
    USE SIGNAL ;
    ANTENNAGATEAREA 0.180700 ;
    PORT
      LAYER Metal2 ;
        RECT 46.360 53.360 46.760 53.760 ;
    END
  END S1END[2]
  PIN S1END[3]
    DIRECTION INPUT ;
    USE SIGNAL ;
    ANTENNAGATEAREA 0.180700 ;
    PORT
      LAYER Metal2 ;
        RECT 47.320 53.360 47.720 53.760 ;
    END
  END S1END[3]
  PIN S2END[0]
    DIRECTION INPUT ;
    USE SIGNAL ;
    ANTENNAGATEAREA 0.180700 ;
    PORT
      LAYER Metal2 ;
        RECT 55.960 53.360 56.360 53.760 ;
    END
  END S2END[0]
  PIN S2END[1]
    DIRECTION INPUT ;
    USE SIGNAL ;
    ANTENNAGATEAREA 0.180700 ;
    PORT
      LAYER Metal2 ;
        RECT 56.920 53.360 57.320 53.760 ;
    END
  END S2END[1]
  PIN S2END[2]
    DIRECTION INPUT ;
    USE SIGNAL ;
    ANTENNAGATEAREA 0.180700 ;
    PORT
      LAYER Metal2 ;
        RECT 57.880 53.360 58.280 53.760 ;
    END
  END S2END[2]
  PIN S2END[3]
    DIRECTION INPUT ;
    USE SIGNAL ;
    ANTENNAGATEAREA 0.180700 ;
    PORT
      LAYER Metal2 ;
        RECT 58.840 53.360 59.240 53.760 ;
    END
  END S2END[3]
  PIN S2END[4]
    DIRECTION INPUT ;
    USE SIGNAL ;
    ANTENNAGATEAREA 0.180700 ;
    PORT
      LAYER Metal2 ;
        RECT 59.800 53.360 60.200 53.760 ;
    END
  END S2END[4]
  PIN S2END[5]
    DIRECTION INPUT ;
    USE SIGNAL ;
    ANTENNAGATEAREA 0.180700 ;
    PORT
      LAYER Metal2 ;
        RECT 60.760 53.360 61.160 53.760 ;
    END
  END S2END[5]
  PIN S2END[6]
    DIRECTION INPUT ;
    USE SIGNAL ;
    ANTENNAGATEAREA 0.180700 ;
    PORT
      LAYER Metal2 ;
        RECT 61.720 53.360 62.120 53.760 ;
    END
  END S2END[6]
  PIN S2END[7]
    DIRECTION INPUT ;
    USE SIGNAL ;
    ANTENNAGATEAREA 0.180700 ;
    PORT
      LAYER Metal2 ;
        RECT 62.680 53.360 63.080 53.760 ;
    END
  END S2END[7]
  PIN S2MID[0]
    DIRECTION INPUT ;
    USE SIGNAL ;
    ANTENNAGATEAREA 0.180700 ;
    PORT
      LAYER Metal2 ;
        RECT 48.280 53.360 48.680 53.760 ;
    END
  END S2MID[0]
  PIN S2MID[1]
    DIRECTION INPUT ;
    USE SIGNAL ;
    ANTENNAGATEAREA 0.180700 ;
    PORT
      LAYER Metal2 ;
        RECT 49.240 53.360 49.640 53.760 ;
    END
  END S2MID[1]
  PIN S2MID[2]
    DIRECTION INPUT ;
    USE SIGNAL ;
    ANTENNAGATEAREA 0.180700 ;
    PORT
      LAYER Metal2 ;
        RECT 50.200 53.360 50.600 53.760 ;
    END
  END S2MID[2]
  PIN S2MID[3]
    DIRECTION INPUT ;
    USE SIGNAL ;
    ANTENNAGATEAREA 0.180700 ;
    PORT
      LAYER Metal2 ;
        RECT 51.160 53.360 51.560 53.760 ;
    END
  END S2MID[3]
  PIN S2MID[4]
    DIRECTION INPUT ;
    USE SIGNAL ;
    ANTENNAGATEAREA 0.180700 ;
    PORT
      LAYER Metal2 ;
        RECT 52.120 53.360 52.520 53.760 ;
    END
  END S2MID[4]
  PIN S2MID[5]
    DIRECTION INPUT ;
    USE SIGNAL ;
    ANTENNAGATEAREA 0.180700 ;
    PORT
      LAYER Metal2 ;
        RECT 53.080 53.360 53.480 53.760 ;
    END
  END S2MID[5]
  PIN S2MID[6]
    DIRECTION INPUT ;
    USE SIGNAL ;
    ANTENNAGATEAREA 0.180700 ;
    PORT
      LAYER Metal2 ;
        RECT 54.040 53.360 54.440 53.760 ;
    END
  END S2MID[6]
  PIN S2MID[7]
    DIRECTION INPUT ;
    USE SIGNAL ;
    ANTENNAGATEAREA 0.180700 ;
    PORT
      LAYER Metal2 ;
        RECT 55.000 53.360 55.400 53.760 ;
    END
  END S2MID[7]
  PIN S4END[0]
    DIRECTION INPUT ;
    USE SIGNAL ;
    ANTENNAGATEAREA 0.180700 ;
    PORT
      LAYER Metal2 ;
        RECT 63.640 53.360 64.040 53.760 ;
    END
  END S4END[0]
  PIN S4END[10]
    DIRECTION INPUT ;
    USE SIGNAL ;
    ANTENNAGATEAREA 0.180700 ;
    PORT
      LAYER Metal2 ;
        RECT 73.240 53.360 73.640 53.760 ;
    END
  END S4END[10]
  PIN S4END[11]
    DIRECTION INPUT ;
    USE SIGNAL ;
    ANTENNAGATEAREA 0.180700 ;
    PORT
      LAYER Metal2 ;
        RECT 74.200 53.360 74.600 53.760 ;
    END
  END S4END[11]
  PIN S4END[12]
    DIRECTION INPUT ;
    USE SIGNAL ;
    ANTENNAGATEAREA 0.180700 ;
    PORT
      LAYER Metal2 ;
        RECT 75.160 53.360 75.560 53.760 ;
    END
  END S4END[12]
  PIN S4END[13]
    DIRECTION INPUT ;
    USE SIGNAL ;
    ANTENNAGATEAREA 0.180700 ;
    PORT
      LAYER Metal2 ;
        RECT 76.120 53.360 76.520 53.760 ;
    END
  END S4END[13]
  PIN S4END[14]
    DIRECTION INPUT ;
    USE SIGNAL ;
    ANTENNAGATEAREA 0.180700 ;
    PORT
      LAYER Metal2 ;
        RECT 77.080 53.360 77.480 53.760 ;
    END
  END S4END[14]
  PIN S4END[15]
    DIRECTION INPUT ;
    USE SIGNAL ;
    ANTENNAGATEAREA 0.180700 ;
    PORT
      LAYER Metal2 ;
        RECT 78.040 53.360 78.440 53.760 ;
    END
  END S4END[15]
  PIN S4END[1]
    DIRECTION INPUT ;
    USE SIGNAL ;
    ANTENNAGATEAREA 0.180700 ;
    PORT
      LAYER Metal2 ;
        RECT 64.600 53.360 65.000 53.760 ;
    END
  END S4END[1]
  PIN S4END[2]
    DIRECTION INPUT ;
    USE SIGNAL ;
    ANTENNAGATEAREA 0.180700 ;
    PORT
      LAYER Metal2 ;
        RECT 65.560 53.360 65.960 53.760 ;
    END
  END S4END[2]
  PIN S4END[3]
    DIRECTION INPUT ;
    USE SIGNAL ;
    ANTENNAGATEAREA 0.180700 ;
    PORT
      LAYER Metal2 ;
        RECT 66.520 53.360 66.920 53.760 ;
    END
  END S4END[3]
  PIN S4END[4]
    DIRECTION INPUT ;
    USE SIGNAL ;
    ANTENNAGATEAREA 0.180700 ;
    PORT
      LAYER Metal2 ;
        RECT 67.480 53.360 67.880 53.760 ;
    END
  END S4END[4]
  PIN S4END[5]
    DIRECTION INPUT ;
    USE SIGNAL ;
    ANTENNAGATEAREA 0.180700 ;
    PORT
      LAYER Metal2 ;
        RECT 68.440 53.360 68.840 53.760 ;
    END
  END S4END[5]
  PIN S4END[6]
    DIRECTION INPUT ;
    USE SIGNAL ;
    ANTENNAGATEAREA 0.180700 ;
    PORT
      LAYER Metal2 ;
        RECT 69.400 53.360 69.800 53.760 ;
    END
  END S4END[6]
  PIN S4END[7]
    DIRECTION INPUT ;
    USE SIGNAL ;
    ANTENNAGATEAREA 0.180700 ;
    PORT
      LAYER Metal2 ;
        RECT 70.360 53.360 70.760 53.760 ;
    END
  END S4END[7]
  PIN S4END[8]
    DIRECTION INPUT ;
    USE SIGNAL ;
    ANTENNAGATEAREA 0.180700 ;
    PORT
      LAYER Metal2 ;
        RECT 71.320 53.360 71.720 53.760 ;
    END
  END S4END[8]
  PIN S4END[9]
    DIRECTION INPUT ;
    USE SIGNAL ;
    ANTENNAGATEAREA 0.180700 ;
    PORT
      LAYER Metal2 ;
        RECT 72.280 53.360 72.680 53.760 ;
    END
  END S4END[9]
  PIN UserCLK
    DIRECTION INPUT ;
    USE SIGNAL ;
    ANTENNAGATEAREA 0.180700 ;
    PORT
      LAYER Metal2 ;
        RECT 6.040 0.000 6.440 0.400 ;
    END
  END UserCLK
  PIN UserCLKo
    DIRECTION OUTPUT ;
    USE SIGNAL ;
    ANTENNADIFFAREA 0.708600 ;
    PORT
      LAYER Metal2 ;
        RECT 79.000 53.360 79.400 53.760 ;
    END
  END UserCLKo
  PIN VGND
    DIRECTION INOUT ;
    USE GROUND ;
    PORT
      LAYER TopMetal1 ;
        RECT 21.580 0.000 23.780 53.760 ;
    END
    PORT
      LAYER TopMetal1 ;
        RECT 97.180 0.000 99.380 53.760 ;
    END
  END VGND
  PIN VPWR
    DIRECTION INOUT ;
    USE POWER ;
    PORT
      LAYER TopMetal1 ;
        RECT 15.380 0.000 17.580 53.760 ;
    END
    PORT
      LAYER TopMetal1 ;
        RECT 90.980 0.000 93.180 53.760 ;
    END
  END VPWR
  OBS
      LAYER GatPoly ;
        RECT 2.880 3.630 106.560 49.290 ;
      LAYER Metal1 ;
        RECT 2.880 3.560 106.560 49.360 ;
      LAYER Metal2 ;
        RECT 4.695 53.150 9.670 53.360 ;
        RECT 10.490 53.150 10.630 53.360 ;
        RECT 11.450 53.150 11.590 53.360 ;
        RECT 12.410 53.150 12.550 53.360 ;
        RECT 13.370 53.150 13.510 53.360 ;
        RECT 14.330 53.150 14.470 53.360 ;
        RECT 15.290 53.150 15.430 53.360 ;
        RECT 16.250 53.150 16.390 53.360 ;
        RECT 17.210 53.150 17.350 53.360 ;
        RECT 18.170 53.150 18.310 53.360 ;
        RECT 19.130 53.150 19.270 53.360 ;
        RECT 20.090 53.150 20.230 53.360 ;
        RECT 21.050 53.150 21.190 53.360 ;
        RECT 22.010 53.150 22.150 53.360 ;
        RECT 22.970 53.150 23.110 53.360 ;
        RECT 23.930 53.150 24.070 53.360 ;
        RECT 24.890 53.150 25.030 53.360 ;
        RECT 25.850 53.150 25.990 53.360 ;
        RECT 26.810 53.150 26.950 53.360 ;
        RECT 27.770 53.150 27.910 53.360 ;
        RECT 28.730 53.150 28.870 53.360 ;
        RECT 29.690 53.150 29.830 53.360 ;
        RECT 30.650 53.150 30.790 53.360 ;
        RECT 31.610 53.150 31.750 53.360 ;
        RECT 32.570 53.150 32.710 53.360 ;
        RECT 33.530 53.150 33.670 53.360 ;
        RECT 34.490 53.150 34.630 53.360 ;
        RECT 35.450 53.150 35.590 53.360 ;
        RECT 36.410 53.150 36.550 53.360 ;
        RECT 37.370 53.150 37.510 53.360 ;
        RECT 38.330 53.150 38.470 53.360 ;
        RECT 39.290 53.150 39.430 53.360 ;
        RECT 40.250 53.150 40.390 53.360 ;
        RECT 41.210 53.150 41.350 53.360 ;
        RECT 42.170 53.150 42.310 53.360 ;
        RECT 43.130 53.150 43.270 53.360 ;
        RECT 44.090 53.150 44.230 53.360 ;
        RECT 45.050 53.150 45.190 53.360 ;
        RECT 46.010 53.150 46.150 53.360 ;
        RECT 46.970 53.150 47.110 53.360 ;
        RECT 47.930 53.150 48.070 53.360 ;
        RECT 48.890 53.150 49.030 53.360 ;
        RECT 49.850 53.150 49.990 53.360 ;
        RECT 50.810 53.150 50.950 53.360 ;
        RECT 51.770 53.150 51.910 53.360 ;
        RECT 52.730 53.150 52.870 53.360 ;
        RECT 53.690 53.150 53.830 53.360 ;
        RECT 54.650 53.150 54.790 53.360 ;
        RECT 55.610 53.150 55.750 53.360 ;
        RECT 56.570 53.150 56.710 53.360 ;
        RECT 57.530 53.150 57.670 53.360 ;
        RECT 58.490 53.150 58.630 53.360 ;
        RECT 59.450 53.150 59.590 53.360 ;
        RECT 60.410 53.150 60.550 53.360 ;
        RECT 61.370 53.150 61.510 53.360 ;
        RECT 62.330 53.150 62.470 53.360 ;
        RECT 63.290 53.150 63.430 53.360 ;
        RECT 64.250 53.150 64.390 53.360 ;
        RECT 65.210 53.150 65.350 53.360 ;
        RECT 66.170 53.150 66.310 53.360 ;
        RECT 67.130 53.150 67.270 53.360 ;
        RECT 68.090 53.150 68.230 53.360 ;
        RECT 69.050 53.150 69.190 53.360 ;
        RECT 70.010 53.150 70.150 53.360 ;
        RECT 70.970 53.150 71.110 53.360 ;
        RECT 71.930 53.150 72.070 53.360 ;
        RECT 72.890 53.150 73.030 53.360 ;
        RECT 73.850 53.150 73.990 53.360 ;
        RECT 74.810 53.150 74.950 53.360 ;
        RECT 75.770 53.150 75.910 53.360 ;
        RECT 76.730 53.150 76.870 53.360 ;
        RECT 77.690 53.150 77.830 53.360 ;
        RECT 78.650 53.150 78.790 53.360 ;
        RECT 79.610 53.150 79.750 53.360 ;
        RECT 80.570 53.150 80.710 53.360 ;
        RECT 81.530 53.150 81.670 53.360 ;
        RECT 82.490 53.150 82.630 53.360 ;
        RECT 83.450 53.150 83.590 53.360 ;
        RECT 84.410 53.150 84.550 53.360 ;
        RECT 85.370 53.150 85.510 53.360 ;
        RECT 86.330 53.150 86.470 53.360 ;
        RECT 87.290 53.150 87.430 53.360 ;
        RECT 88.250 53.150 88.390 53.360 ;
        RECT 89.210 53.150 89.350 53.360 ;
        RECT 90.170 53.150 90.310 53.360 ;
        RECT 91.130 53.150 91.270 53.360 ;
        RECT 92.090 53.150 92.230 53.360 ;
        RECT 93.050 53.150 93.190 53.360 ;
        RECT 94.010 53.150 94.150 53.360 ;
        RECT 94.970 53.150 95.110 53.360 ;
        RECT 95.930 53.150 96.070 53.360 ;
        RECT 96.890 53.150 97.030 53.360 ;
        RECT 97.850 53.150 97.990 53.360 ;
        RECT 98.810 53.150 107.145 53.360 ;
        RECT 4.695 0.610 107.145 53.150 ;
        RECT 4.695 0.100 5.830 0.610 ;
        RECT 6.650 0.100 10.630 0.610 ;
        RECT 11.450 0.100 15.430 0.610 ;
        RECT 16.250 0.100 20.230 0.610 ;
        RECT 21.050 0.100 25.030 0.610 ;
        RECT 25.850 0.100 29.830 0.610 ;
        RECT 30.650 0.100 34.630 0.610 ;
        RECT 35.450 0.100 39.430 0.610 ;
        RECT 40.250 0.100 44.230 0.610 ;
        RECT 45.050 0.100 49.030 0.610 ;
        RECT 49.850 0.100 53.830 0.610 ;
        RECT 54.650 0.100 58.630 0.610 ;
        RECT 59.450 0.100 63.430 0.610 ;
        RECT 64.250 0.100 68.230 0.610 ;
        RECT 69.050 0.100 73.030 0.610 ;
        RECT 73.850 0.100 77.830 0.610 ;
        RECT 78.650 0.100 82.630 0.610 ;
        RECT 83.450 0.100 87.430 0.610 ;
        RECT 88.250 0.100 92.230 0.610 ;
        RECT 93.050 0.100 97.030 0.610 ;
        RECT 97.850 0.100 101.830 0.610 ;
        RECT 102.650 0.100 107.145 0.610 ;
      LAYER Metal3 ;
        RECT 0.380 52.910 109.040 53.445 ;
        RECT 0.610 52.090 108.830 52.910 ;
        RECT 0.380 51.230 109.040 52.090 ;
        RECT 0.610 50.410 108.830 51.230 ;
        RECT 0.380 49.550 109.040 50.410 ;
        RECT 0.610 48.730 108.830 49.550 ;
        RECT 0.380 47.870 109.040 48.730 ;
        RECT 0.610 47.050 108.830 47.870 ;
        RECT 0.380 46.190 109.040 47.050 ;
        RECT 0.610 45.370 108.830 46.190 ;
        RECT 0.380 44.510 109.040 45.370 ;
        RECT 0.610 43.690 108.830 44.510 ;
        RECT 0.380 42.830 109.040 43.690 ;
        RECT 0.610 42.010 108.830 42.830 ;
        RECT 0.380 41.150 109.040 42.010 ;
        RECT 0.610 40.330 108.830 41.150 ;
        RECT 0.380 39.470 109.040 40.330 ;
        RECT 0.610 38.650 108.830 39.470 ;
        RECT 0.380 37.790 109.040 38.650 ;
        RECT 0.610 36.970 108.830 37.790 ;
        RECT 0.380 36.110 109.040 36.970 ;
        RECT 0.610 35.290 108.830 36.110 ;
        RECT 0.380 34.430 109.040 35.290 ;
        RECT 0.610 33.610 108.830 34.430 ;
        RECT 0.380 32.750 109.040 33.610 ;
        RECT 0.610 31.930 108.830 32.750 ;
        RECT 0.380 31.070 109.040 31.930 ;
        RECT 0.610 30.250 108.830 31.070 ;
        RECT 0.380 29.390 109.040 30.250 ;
        RECT 0.610 28.570 108.830 29.390 ;
        RECT 0.380 27.710 109.040 28.570 ;
        RECT 0.610 26.890 108.830 27.710 ;
        RECT 0.380 26.030 109.040 26.890 ;
        RECT 0.610 25.210 108.830 26.030 ;
        RECT 0.380 24.350 109.040 25.210 ;
        RECT 0.610 23.530 108.830 24.350 ;
        RECT 0.380 22.670 109.040 23.530 ;
        RECT 0.610 21.850 108.830 22.670 ;
        RECT 0.380 20.990 109.040 21.850 ;
        RECT 0.610 20.170 108.830 20.990 ;
        RECT 0.380 19.310 109.040 20.170 ;
        RECT 0.610 18.490 108.830 19.310 ;
        RECT 0.380 17.630 109.040 18.490 ;
        RECT 0.610 16.810 108.830 17.630 ;
        RECT 0.380 15.950 109.040 16.810 ;
        RECT 0.610 15.130 108.830 15.950 ;
        RECT 0.380 14.270 109.040 15.130 ;
        RECT 0.610 13.450 108.830 14.270 ;
        RECT 0.380 12.590 109.040 13.450 ;
        RECT 0.610 11.770 108.830 12.590 ;
        RECT 0.380 10.910 109.040 11.770 ;
        RECT 0.610 10.090 108.830 10.910 ;
        RECT 0.380 9.230 109.040 10.090 ;
        RECT 0.610 8.410 108.830 9.230 ;
        RECT 0.380 7.550 109.040 8.410 ;
        RECT 0.610 6.730 108.830 7.550 ;
        RECT 0.380 5.870 109.040 6.730 ;
        RECT 0.610 5.050 108.830 5.870 ;
        RECT 0.380 4.190 109.040 5.050 ;
        RECT 0.610 3.370 108.830 4.190 ;
        RECT 0.380 2.510 109.040 3.370 ;
        RECT 0.610 1.690 108.830 2.510 ;
        RECT 0.380 0.830 109.040 1.690 ;
        RECT 0.610 0.320 108.830 0.830 ;
      LAYER Metal4 ;
        RECT 9.975 3.635 101.385 53.485 ;
      LAYER Metal5 ;
        RECT 9.935 3.470 101.425 50.920 ;
  END
END S_term_IHP_SRAM
END LIBRARY

